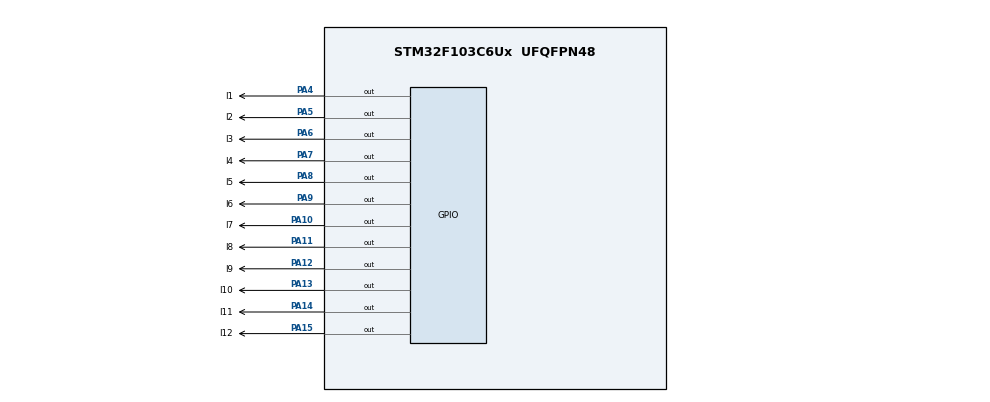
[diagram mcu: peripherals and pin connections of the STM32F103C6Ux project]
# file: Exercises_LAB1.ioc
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Mcu.Family=STM32F1
Mcu.Name=STM32F103C6Ux
Mcu.Package=UFQFPN48
NVIC.PriorityGroup=NVIC_PRIORITYGROUP_4
PA10.GPIO_Label=l7
PA10.Signal=GPIO_Output
PA11.GPIO_Label=l8
PA11.Signal=GPIO_Output
PA12.GPIO_Label=l9
PA12.Signal=GPIO_Output
PA13.GPIO_Label=l10
PA13.Signal=GPIO_Output
PA14.GPIO_Label=l11
PA14.Signal=GPIO_Output
PA15.GPIO_Label=l12
PA15.Signal=GPIO_Output
PA4.GPIO_Label=l1
PA4.Signal=GPIO_Output
PA5.GPIO_Label=l2
PA5.Signal=GPIO_Output
PA6.GPIO_Label=l3
PA6.Signal=GPIO_Output
PA7.GPIO_Label=l4
PA7.Signal=GPIO_Output
PA8.GPIO_Label=l5
PA8.Signal=GPIO_Output
PA9.GPIO_Label=l6
PA9.Signal=GPIO_Output
ProjectManager.HeapSize=0x200
ProjectManager.StackSize=0x400
ProjectManager.TargetToolchain=STM32CubeIDE
RCC.APB1Freq_Value=8000000
RCC.APB2Freq_Value=8000000
VP_SYS_VS_ND.Mode=No_Debug
board=custom

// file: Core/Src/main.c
/* USER CODE BEGIN Header */
/**
  ******************************************************************************
  * @file           : main.c
  * @brief          : Main program body
  ******************************************************************************
  * @attention
  *
  * <h2><center>&copy; Copyright (c) 2023 STMicroelectronics.
  * All rights reserved.</center></h2>
  *
  * This software component is licensed by ST under BSD 3-Clause license,
  * the "License"; You may not use this file except in compliance with the
  * License. You may obtain a copy of the License at:
  *                        opensource.org/licenses/BSD-3-Clause
  *
  ******************************************************************************
  */
/* USER CODE END Header */
#include "main.h"

//#include "software_timer.c"
#include "software_timer.h"//ADD

void SystemClock_Config(void);
static void MX_GPIO_Init(void);

int timer1_counter = 0;
int timer2_counter = 0;
int timer1_flag = 0;

void setTimer1(int duration)
{
	timer1_counter = duration;
	timer1_flag = 0;
}

void timerRun()
{
	if(timer1_counter > 0)
	{
		timer1_counter--;
		if(timer1_counter <= 0)
		{
			timer1_flag = 1;
		}
	}
}//ADD

GPIO_TypeDef* seg_port[] = {a_GPIO_Port, b_GPIO_Port, c_GPIO_Port, d_GPIO_Port, e_GPIO_Port, f_GPIO_Port, g_GPIO_Port};
int seg_pin[] = {a_Pin, b_Pin, c_Pin, d_Pin, e_Pin, f_Pin, g_Pin};

int seg_config[10] = {0x01, 0x4F, 0x12, 0x06, 0x4C, 0x24, 0x20, 0x0F, 0x00, 0x04};

void display7SEG(int num)
{
	GPIOB->ODR = seg_config[num];
}

int main(void)
{

  /* MCU Configuration--------------------------------------------------------*/

  /* Reset of all peripherals, Initializes the Flash interface and the Systick. */
  HAL_Init();

  /* Configure the system clock */
  SystemClock_Config();

  /* Initialize all configured peripherals */
  MX_GPIO_Init();

  /* Infinite loop */
  /* USER CODE BEGIN WHILE */

  setTimer1(500);
//  int counter_led = 9;
  while (1)
  {
  	  if(timer1_counter % 100 == 0 && timer1_counter > 0)
  	  {
  		  display7SEG(timer1_counter / 100);
  	  }
  	  else
  	  {
  		  display7SEG(timer1_counter / 100 + 1);
  	  }

//	  if(timer1_counter % 100 == 0)
//	  {
//		  display7SEG(counter_led);
//		  counter_led--;
//		  if(counter_led < 0)
//			  counter_led = 9;
//	  }

	  if(timer1_flag == 1)
	  {
		  HAL_GPIO_WritePin(red1_GPIO_Port, red1_Pin, SET);
		  HAL_GPIO_WritePin(yellow1_GPIO_Port, yellow1_Pin, RESET);
		  HAL_GPIO_WritePin(green1_GPIO_Port, green1_Pin, RESET);

		  if(timer1_counter <= 0 && timer2_counter == 0)
		  {
			  setTimer1(300);
			  timer1_flag = 1;
			  timer2_counter++;
		  }
		  if(timer1_counter > 0 && timer2_counter == 1)
		  {
			  HAL_GPIO_WritePin(red_GPIO_Port, red_Pin, RESET);
			  HAL_GPIO_WritePin(yellow_GPIO_Port, yellow_Pin, RESET);
			  HAL_GPIO_WritePin(green_GPIO_Port, green_Pin, SET);
		  }
		  if(timer1_counter <= 0 && timer2_counter == 1)
		  {
			  timer2_counter++;
			  setTimer1(200);
			  timer1_flag = 1;
		  }
		  if(timer2_counter == 2)
		  {
			  HAL_GPIO_WritePin(red_GPIO_Port, red_Pin, RESET);
			  HAL_GPIO_WritePin(yellow_GPIO_Port, yellow_Pin, SET);
			  HAL_GPIO_WritePin(green_GPIO_Port, green_Pin, RESET);
			  if(timer1_counter <= 0)
			  {
				  timer2_counter = 0;
				  setTimer1(500);
			  }
		  }
	  }
	  else
	  {
		  HAL_GPIO_WritePin(red_GPIO_Port, red_Pin, SET);
		  HAL_GPIO_WritePin(yellow_GPIO_Port, yellow_Pin, RESET);
		  HAL_GPIO_WritePin(green_GPIO_Port, green_Pin, RESET);
		  if(timer1_counter <= 200 )
		  {
			  HAL_GPIO_WritePin(red1_GPIO_Port, red1_Pin, RESET);
			  HAL_GPIO_WritePin(yellow1_GPIO_Port, yellow1_Pin, SET);
			  HAL_GPIO_WritePin(green1_GPIO_Port, green1_Pin, RESET);
		  }
		  else
		  {
			  HAL_GPIO_WritePin(red1_GPIO_Port, red1_Pin, RESET);
			  HAL_GPIO_WritePin(yellow1_GPIO_Port, yellow1_Pin, RESET);
			  HAL_GPIO_WritePin(green1_GPIO_Port, green1_Pin, SET);
		  }
	  }

	  timerRun();
	  HAL_Delay(10);

    /* USER CODE END WHILE */

  }
}

void SystemClock_Config(void)
{
  RCC_OscInitTypeDef RCC_OscInitStruct = {0};
  RCC_ClkInitTypeDef RCC_ClkInitStruct = {0};

  /** Initializes the RCC Oscillators according to the specified parameters
  * in the RCC_OscInitTypeDef structure.
  */
  RCC_OscInitStruct.OscillatorType = RCC_OSCILLATORTYPE_HSI;
  RCC_OscInitStruct.HSIState = RCC_HSI_ON;
  RCC_OscInitStruct.HSICalibrationValue = RCC_HSICALIBRATION_DEFAULT;
  RCC_OscInitStruct.PLL.PLLState = RCC_PLL_NONE;
  if (HAL_RCC_OscConfig(&RCC_OscInitStruct) != HAL_OK)
  {
    Error_Handler();
  }
  /** Initializes the CPU, AHB and APB buses clocks
  */
  RCC_ClkInitStruct.ClockType = RCC_CLOCKTYPE_HCLK|RCC_CLOCKTYPE_SYSCLK
                              |RCC_CLOCKTYPE_PCLK1|RCC_CLOCKTYPE_PCLK2;
  RCC_ClkInitStruct.SYSCLKSource = RCC_SYSCLKSOURCE_HSI;
  RCC_ClkInitStruct.AHBCLKDivider = RCC_SYSCLK_DIV1;
  RCC_ClkInitStruct.APB1CLKDivider = RCC_HCLK_DIV1;
  RCC_ClkInitStruct.APB2CLKDivider = RCC_HCLK_DIV1;

  if (HAL_RCC_ClockConfig(&RCC_ClkInitStruct, FLASH_LATENCY_0) != HAL_OK)
  {
    Error_Handler();
  }
}

static void MX_GPIO_Init(void)
{
  GPIO_InitTypeDef GPIO_InitStruct = {0};

  /* GPIO Ports Clock Enable */
  __HAL_RCC_GPIOA_CLK_ENABLE();
  __HAL_RCC_GPIOB_CLK_ENABLE();

  /*Configure GPIO pin Output Level */
  HAL_GPIO_WritePin(GPIOA, red_Pin|yellow_Pin|green_Pin|red1_Pin
                          |yellow1_Pin|green1_Pin, GPIO_PIN_RESET);

  /*Configure GPIO pin Output Level */
  HAL_GPIO_WritePin(GPIOB, g_Pin|f_Pin|e_Pin|d_Pin
                          |c_Pin|b_Pin|a_Pin, GPIO_PIN_RESET);

  /*Configure GPIO pins : red_Pin yellow_Pin green_Pin red1_Pin
                           yellow1_Pin green1_Pin */
  GPIO_InitStruct.Pin = red_Pin|yellow_Pin|green_Pin|red1_Pin
                          |yellow1_Pin|green1_Pin;
  GPIO_InitStruct.Mode = GPIO_MODE_OUTPUT_PP;
  GPIO_InitStruct.Pull = GPIO_NOPULL;
  GPIO_InitStruct.Speed = GPIO_SPEED_FREQ_LOW;
  HAL_GPIO_Init(GPIOA, &GPIO_InitStruct);

  /*Configure GPIO pins : g_Pin f_Pin e_Pin d_Pin
                           c_Pin b_Pin a_Pin */
  GPIO_InitStruct.Pin = g_Pin|f_Pin|e_Pin|d_Pin
                          |c_Pin|b_Pin|a_Pin;
  GPIO_InitStruct.Mode = GPIO_MODE_OUTPUT_PP;
  GPIO_InitStruct.Pull = GPIO_NOPULL;
  GPIO_InitStruct.Speed = GPIO_SPEED_FREQ_LOW;
  HAL_GPIO_Init(GPIOB, &GPIO_InitStruct);

}

void Error_Handler(void)
{
  __disable_irq();
  while (1)
  {
  }
}

/************************ (C) COPYRIGHT STMicroelectronics *****END OF FILE****/
